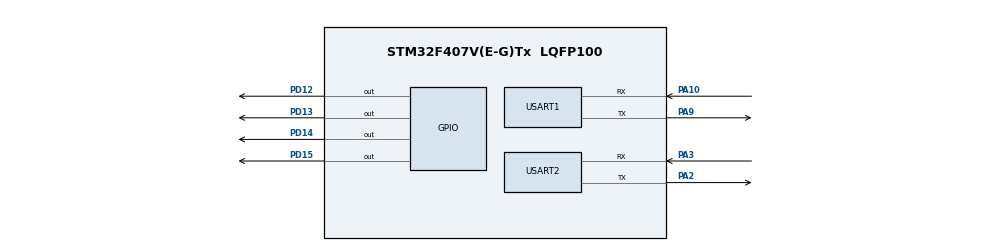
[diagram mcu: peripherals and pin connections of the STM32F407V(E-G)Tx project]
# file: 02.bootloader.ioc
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Mcu.Family=STM32F4
Mcu.Name=STM32F407V(E-G)Tx
Mcu.Package=LQFP100
NVIC.PriorityGroup=NVIC_PRIORITYGROUP_0
NVIC.USART1_IRQn=true\:0\:0\:false\:false\:true\:true
NVIC.USART2_IRQn=true\:0\:0\:false\:false\:true\:true
PA10.Mode=Asynchronous
PA10.Signal=USART1_RX
PA13.Mode=Serial_Wire
PA13.Signal=SYS_JTMS-SWDIO
PA14.Mode=Serial_Wire
PA14.Signal=SYS_JTCK-SWCLK
PA2.Mode=Asynchronous
PA2.Signal=USART2_TX
PA3.Mode=Asynchronous
PA3.Signal=USART2_RX
PA9.Mode=Asynchronous
PA9.Signal=USART1_TX
PD12.Signal=GPIO_Output
PD13.Signal=GPIO_Output
PD14.Signal=GPIO_Output
PD15.Signal=GPIO_Output
PH0-OSC_IN.Mode=HSE-External-Oscillator
PH0-OSC_IN.Signal=RCC_OSC_IN
PH1-OSC_OUT.Mode=HSE-External-Oscillator
PH1-OSC_OUT.Signal=RCC_OSC_OUT
ProjectManager.HeapSize=0x200
ProjectManager.StackSize=0x400
ProjectManager.TargetToolchain=MDK-ARM V5
RCC.48MHZClocksFreq_Value=48000000
RCC.AHBFreq_Value=168000000
RCC.APB1CLKDivider=RCC_HCLK_DIV4
RCC.APB1Freq_Value=42000000
RCC.APB1TimFreq_Value=84000000
RCC.APB2CLKDivider=RCC_HCLK_DIV4
RCC.APB2Freq_Value=42000000
RCC.APB2TimFreq_Value=84000000
RCC.CortexFreq_Value=168000000
RCC.HCLKFreq_Value=168000000
RCC.HSE_VALUE=8000000
RCC.HSI_VALUE=16000000
RCC.LSE_VALUE=32768
RCC.PLLM=8
RCC.PLLN=336
RCC.PLLQ=7
RCC.PLLSourceVirtual=RCC_PLLSOURCE_HSE
RCC.SYSCLKFreq_VALUE=168000000
RCC.SYSCLKSource=RCC_SYSCLKSOURCE_PLLCLK
RCC.VCOOutputFreq_Value=336000000
USART1.VirtualMode=VM_ASYNC
USART2.VirtualMode=VM_ASYNC
board=STM32F4DISCOVERY

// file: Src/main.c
/**
  ******************************************************************************
  * File Name          : main.c
  * Description        : Main program body
  ******************************************************************************
  ** This notice applies to any and all portions of this file
  * that are not between comment pairs USER CODE BEGIN and
  * USER CODE END. Other portions of this file, whether
  * inserted by the user or by software development tools
  * are owned by their respective copyright owners.
  *
  * COPYRIGHT(c) 2022 STMicroelectronics
  *
  * Redistribution and use in source and binary forms, with or without modification,
  * are permitted provided that the following conditions are met:
  *   1. Redistributions of source code must retain the above copyright notice,
  *      this list of conditions and the following disclaimer.
  *   2. Redistributions in binary form must reproduce the above copyright notice,
  *      this list of conditions and the following disclaimer in the documentation
  *      and/or other materials provided with the distribution.
  *   3. Neither the name of STMicroelectronics nor the names of its contributors
  *      may be used to endorse or promote products derived from this software
  *      without specific prior written permission.
  *
  * THIS SOFTWARE IS PROVIDED BY THE COPYRIGHT HOLDERS AND CONTRIBUTORS "AS IS"
  * AND ANY EXPRESS OR IMPLIED WARRANTIES, INCLUDING, BUT NOT LIMITED TO, THE
  * IMPLIED WARRANTIES OF MERCHANTABILITY AND FITNESS FOR A PARTICULAR PURPOSE ARE
  * DISCLAIMED. IN NO EVENT SHALL THE COPYRIGHT HOLDER OR CONTRIBUTORS BE LIABLE
  * FOR ANY DIRECT, INDIRECT, INCIDENTAL, SPECIAL, EXEMPLARY, OR CONSEQUENTIAL
  * DAMAGES (INCLUDING, BUT NOT LIMITED TO, PROCUREMENT OF SUBSTITUTE GOODS OR
  * SERVICES; LOSS OF USE, DATA, OR PROFITS; OR BUSINESS INTERRUPTION) HOWEVER
  * CAUSED AND ON ANY THEORY OF LIABILITY, WHETHER IN CONTRACT, STRICT LIABILITY,
  * OR TORT (INCLUDING NEGLIGENCE OR OTHERWISE) ARISING IN ANY WAY OUT OF THE USE
  * OF THIS SOFTWARE, EVEN IF ADVISED OF THE POSSIBILITY OF SUCH DAMAGE.
  *
  ******************************************************************************
  */

#include "main.h"
#include "stm32f4xx_hal.h"

/* USER CODE BEGIN Includes */
#include "config.h"
#include "debug.h"
#include "bootloader_process.h"
/* USER CODE END Includes */

IWDG_HandleTypeDef hiwdg;

UART_HandleTypeDef huart1;
UART_HandleTypeDef huart2;

/* USER CODE BEGIN PV */
/* Private variables ---------------------------------------------------------*/

/* USER CODE END PV */

void SystemClock_Config(void);
static void MX_GPIO_Init(void);
static void MX_USART1_UART_Init(void);
static void MX_USART2_UART_Init(void);
static void MX_IWDG_Init(void);

/* USER CODE BEGIN PFP */
/* Private function prototypes -----------------------------------------------*/

/* USER CODE END PFP */

/* USER CODE BEGIN 0 */

void led_indicate(void);
void dfu_reinit(void);

char compile_date[] = "Compile Date: " __DATE__;
char compile_time[] = "Compile Time: " __TIME__;

typedef struct {
	uint8_t xC;
	uint8_t buffer[256];
	uint16_t count;
} sSerialData_t;
/*
struct {
	uint8_t xC;
	uint8_t rx_buffer[256];
	uint16_t rx_count;
} uart1_data;
*/
sSerialData_t dfu_rx;
int xCount = 0;
/* USER CODE END 0 */

int main(void)
{

  /* MCU Configuration----------------------------------------------------------*/

  /* Reset of all peripherals, Initializes the Flash interface and the Systick. */
  HAL_Init();

  /* Configure the system clock */
  SystemClock_Config();

  /* Initialize all configured peripherals */
  MX_GPIO_Init();
	#if DEBUG_ENB
  MX_USART1_UART_Init();
	#endif
  MX_USART2_UART_Init();
  MX_IWDG_Init();

  /* USER CODE BEGIN 2 */
	LREP_INFO(__func__, "%s", compile_date);
	LREP(__func__, "%s", compile_time);
	static uint32_t sysTick = 0;
	memset(&dfu_rx, 0, sizeof(sSerialData_t));
	boot_process_init();
	HAL_UART_Receive_IT(&UART_DFU, &dfu_rx.xC, 1);
	//HAL_UART_Receive_DMA(&UART_DFU, &dfu_rx.xC, 1);
  /* USER CODE END 2 */

  /* Infinite loop */
  while (1)
  {

  /* USER CODE BEGIN 3 */
		sysTick = HAL_GetTick();
		#if 1
		if (sysTick > 1000 && !g_DFU_Control.bBoothooked) {
			//JUMP_TO_APP(APP_START_ADDRESS);
			#if DEBUG_ENB
			HAL_UART_DeInit(&huart1);
			#endif
			HAL_UART_DeInit(&huart2);
			HAL_RCC_DeInit();
			boot_jump((uint32_t)APP_START_ADDRESS);
		}
		else {
			//led_indicate();
			HAL_IWDG_Refresh(&hiwdg);
			HAL_Delay(200);
			LREP(__func__, "bootloader app %d", xCount);
			if (xCount == 0) dfu_reinit();
			xCount = 0;
		}
		#else
		LREP(__func__, "bootloader app");
		HAL_UART_Receive_IT(&UART_DFU, (uint8_t*)&dfu_rx.xC, 1);
		HAL_Delay(100);
		#endif
  }
  /* USER CODE END 3 */

}

/** System Clock Configuration
*/
void SystemClock_Config(void)
{

  RCC_OscInitTypeDef RCC_OscInitStruct;
  RCC_ClkInitTypeDef RCC_ClkInitStruct;

    /**Configure the main internal regulator output voltage
    */
  __HAL_RCC_PWR_CLK_ENABLE();

  __HAL_PWR_VOLTAGESCALING_CONFIG(PWR_REGULATOR_VOLTAGE_SCALE1);

    /**Initializes the CPU, AHB and APB busses clocks
    */
  RCC_OscInitStruct.OscillatorType = RCC_OSCILLATORTYPE_HSI|RCC_OSCILLATORTYPE_LSI;
  RCC_OscInitStruct.HSIState = RCC_HSI_ON;
  RCC_OscInitStruct.HSICalibrationValue = 16;
  RCC_OscInitStruct.LSIState = RCC_LSI_ON;
  RCC_OscInitStruct.PLL.PLLState = RCC_PLL_ON;
  RCC_OscInitStruct.PLL.PLLSource = RCC_PLLSOURCE_HSI;
  RCC_OscInitStruct.PLL.PLLM = 8;
  RCC_OscInitStruct.PLL.PLLN = 168;
  RCC_OscInitStruct.PLL.PLLP = RCC_PLLP_DIV2;
  RCC_OscInitStruct.PLL.PLLQ = 7;
  if (HAL_RCC_OscConfig(&RCC_OscInitStruct) != HAL_OK)
  {
    _Error_Handler(__FILE__, __LINE__);
  }

    /**Initializes the CPU, AHB and APB busses clocks
    */
  RCC_ClkInitStruct.ClockType = RCC_CLOCKTYPE_HCLK|RCC_CLOCKTYPE_SYSCLK
                              |RCC_CLOCKTYPE_PCLK1|RCC_CLOCKTYPE_PCLK2;
  RCC_ClkInitStruct.SYSCLKSource = RCC_SYSCLKSOURCE_PLLCLK;
  RCC_ClkInitStruct.AHBCLKDivider = RCC_SYSCLK_DIV1;
  RCC_ClkInitStruct.APB1CLKDivider = RCC_HCLK_DIV4;
  RCC_ClkInitStruct.APB2CLKDivider = RCC_HCLK_DIV2;

  if (HAL_RCC_ClockConfig(&RCC_ClkInitStruct, FLASH_LATENCY_5) != HAL_OK)
  {
    _Error_Handler(__FILE__, __LINE__);
  }

    /**Configure the Systick interrupt time
    */
  HAL_SYSTICK_Config(HAL_RCC_GetHCLKFreq()/1000);

    /**Configure the Systick
    */
  HAL_SYSTICK_CLKSourceConfig(SYSTICK_CLKSOURCE_HCLK);

  /* SysTick_IRQn interrupt configuration */
  HAL_NVIC_SetPriority(SysTick_IRQn, 0, 0);
}

/* IWDG init function */
static void MX_IWDG_Init(void)
{

  hiwdg.Instance = IWDG;
  hiwdg.Init.Prescaler = IWDG_PRESCALER_32; //IWDG_PRESCALER_4;
  hiwdg.Init.Reload = 2000; //4095;
  if (HAL_IWDG_Init(&hiwdg) != HAL_OK)
  {
    _Error_Handler(__FILE__, __LINE__);
  }

}

/* USART1 init function */
static void MX_USART1_UART_Init(void)
{

  huart1.Instance = USART1;
  huart1.Init.BaudRate = 115200;
  huart1.Init.WordLength = UART_WORDLENGTH_8B;
  huart1.Init.StopBits = UART_STOPBITS_1;
  huart1.Init.Parity = UART_PARITY_NONE;
  huart1.Init.Mode = UART_MODE_TX_RX;
  huart1.Init.HwFlowCtl = UART_HWCONTROL_NONE;
  huart1.Init.OverSampling = UART_OVERSAMPLING_16;
  if (HAL_UART_Init(&huart1) != HAL_OK)
  {
    _Error_Handler(__FILE__, __LINE__);
  }

}

/* USART2 init function */
static void MX_USART2_UART_Init(void)
{

  huart2.Instance = USART2;
  huart2.Init.BaudRate = 115200;
  huart2.Init.WordLength = UART_WORDLENGTH_8B;
  huart2.Init.StopBits = UART_STOPBITS_1;
  huart2.Init.Parity = UART_PARITY_NONE;
  huart2.Init.Mode = UART_MODE_TX_RX;
  huart2.Init.HwFlowCtl = UART_HWCONTROL_NONE;
  huart2.Init.OverSampling = UART_OVERSAMPLING_16;
  if (HAL_UART_Init(&huart2) != HAL_OK)
  {
    _Error_Handler(__FILE__, __LINE__);
  }

}

/** Configure pins as
        * Analog
        * Input
        * Output
        * EVENT_OUT
        * EXTI
*/
static void MX_GPIO_Init(void)
{

  /* GPIO Ports Clock Enable */
//  __HAL_RCC_GPIOH_CLK_ENABLE();
  __HAL_RCC_GPIOA_CLK_ENABLE();

}

/* USER CODE BEGIN 4 */
void led_indicate(void) {
	static int led_count = 0;
	led_count++;
	if (led_count == 1) {
		HAL_GPIO_WritePin(GPIOD, GPIO_PIN_12 | GPIO_PIN_13 | GPIO_PIN_14 | GPIO_PIN_15, GPIO_PIN_RESET);
		HAL_GPIO_WritePin(GPIOD, GPIO_PIN_12, GPIO_PIN_SET);
	}
	else if (led_count == 2) {
		HAL_GPIO_WritePin(GPIOD, GPIO_PIN_12 | GPIO_PIN_13 | GPIO_PIN_14 | GPIO_PIN_15, GPIO_PIN_RESET);
		HAL_GPIO_WritePin(GPIOD, GPIO_PIN_13, GPIO_PIN_SET);
	}
	else if (led_count == 3) {
		HAL_GPIO_WritePin(GPIOD, GPIO_PIN_12 | GPIO_PIN_13 | GPIO_PIN_14 | GPIO_PIN_15, GPIO_PIN_RESET);
		HAL_GPIO_WritePin(GPIOD, GPIO_PIN_14, GPIO_PIN_SET);
	}
	else if (led_count == 4) {
		HAL_GPIO_WritePin(GPIOD, GPIO_PIN_12 | GPIO_PIN_13 | GPIO_PIN_14 | GPIO_PIN_15, GPIO_PIN_RESET);
		HAL_GPIO_WritePin(GPIOD, GPIO_PIN_15, GPIO_PIN_SET);
	}
	else led_count = 0;
}

void HAL_UART_RxCpltCallback(UART_HandleTypeDef *huart) {
	if (huart->Instance == DFU_UART_INSTANCE) {
		xCount++;
		dfu_rx.buffer[dfu_rx.count++] = dfu_rx.xC;
		if (dfu_rx.xC == RECORD_EOF) {
			boot_process_line(dfu_rx.buffer, dfu_rx.count);
			memset(&dfu_rx, 0, sizeof(sSerialData_t));
		}
		else if (dfu_rx.count > 255) {
			LREP_WARNING("UART2_RX_CB", "msg too long");
			memset(&dfu_rx, 0, sizeof(sSerialData_t));
		}
		HAL_UART_Receive_IT(&UART_DFU, (uint8_t*)&dfu_rx.xC, 1);
	}
}

void HAL_UART_ErrorCallback(UART_HandleTypeDef *huart) {
	if (huart->Instance == DFU_UART_INSTANCE) {
		LREP_ERROR(__func__, "DFU UART Error %d", huart->ErrorCode);

		//dfu_reinit();
		//HAL_UART_Receive_DMA(&UART_DFU, &dfu_rx.xC, 1);
	}
}

void dfu_reinit(void) {
	if (HAL_UART_DeInit(&UART_DFU) != HAL_OK) {
		LREP_ERROR(__func__, "Deinit error");
	}
	if (HAL_UART_Init(&UART_DFU) != HAL_OK) {
		LREP_ERROR(__func__, "Init error");
	}

	HAL_UART_Receive_IT(&UART_DFU, (uint8_t*)&dfu_rx.xC, 1);
}

/* USER CODE END 4 */

void _Error_Handler(char * file, int line)
{
  while(1)
  {
  }
}

/************************ (C) COPYRIGHT STMicroelectronics *****END OF FILE****/
